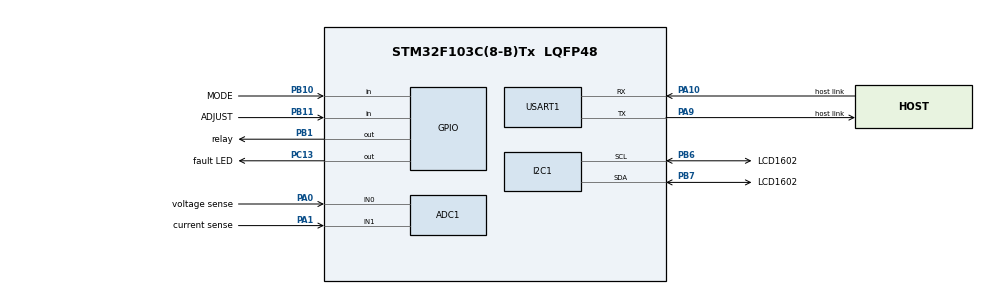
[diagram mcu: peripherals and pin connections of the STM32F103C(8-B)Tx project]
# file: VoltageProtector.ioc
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ADC1.Channel-1\#ChannelRegularConversion=ADC_CHANNEL_0
ADC1.NbrOfConversionFlag=1
ADC1.Rank-1\#ChannelRegularConversion=1
ADC1.SamplingTime-1\#ChannelRegularConversion=ADC_SAMPLETIME_1CYCLE_5
ADC1.master=1
Mcu.Family=STM32F1
Mcu.Name=STM32F103C(8-B)Tx
Mcu.Package=LQFP48
NVIC.PriorityGroup=NVIC_PRIORITYGROUP_4
NVIC.USART1_IRQn=true\:0\:0\:false\:false\:true\:true\:true\:true
PA0-WKUP.GPIO_Label=voltage sense
PA0-WKUP.Signal=ADCx_IN0
PA1.GPIO_Label=current sense
PA1.Signal=ADCx_IN1
PA10.GPIO_Label=host link
PA10.Mode=Asynchronous
PA10.Signal=USART1_RX
PA13.Mode=Serial_Wire
PA13.Signal=SYS_JTMS-SWDIO
PA14.Mode=Serial_Wire
PA14.Signal=SYS_JTCK-SWCLK
PA9.GPIO_Label=host link
PA9.Mode=Asynchronous
PA9.Signal=USART1_TX
PB1.GPIO_Label=relay
PB1.Signal=GPIO_Output
PB10.GPIO_Label=MODE
PB10.Signal=GPIO_Input
PB11.GPIO_Label=ADJUST
PB11.Signal=GPIO_Input
PB6.GPIO_Label=LCD1602
PB6.Mode=I2C
PB6.Signal=I2C1_SCL
PB7.GPIO_Label=LCD1602
PB7.Mode=I2C
PB7.Signal=I2C1_SDA
PC13-TAMPER-RTC.GPIO_Label=fault LED
PC13-TAMPER-RTC.Signal=GPIO_Output
PD0-OSC_IN.Mode=HSE-External-Oscillator
PD0-OSC_IN.Signal=RCC_OSC_IN
PD1-OSC_OUT.Mode=HSE-External-Oscillator
PD1-OSC_OUT.Signal=RCC_OSC_OUT
ProjectManager.HeapSize=0x200
ProjectManager.StackSize=0x400
ProjectManager.TargetToolchain=STM32CubeIDE
RCC.ADCPresc=RCC_ADCPCLK2_DIV6
RCC.AHBFreq_Value=72000000
RCC.APB1CLKDivider=RCC_HCLK_DIV2
RCC.APB1Freq_Value=36000000
RCC.APB1TimFreq_Value=72000000
RCC.APB2Freq_Value=72000000
RCC.APB2TimFreq_Value=72000000
RCC.HCLKFreq_Value=72000000
RCC.PLLMUL=RCC_PLL_MUL9
RCC.PLLSourceVirtual=RCC_PLLSOURCE_HSE
RCC.SYSCLKFreq_VALUE=72000000
RCC.SYSCLKSource=RCC_SYSCLKSOURCE_PLLCLK
RCC.USBFreq_Value=72000000
SH.ADCx_IN0.0=ADC1_IN0,IN0
SH.ADCx_IN1.0=ADC1_IN1,IN1
USART1.VirtualMode=VM_ASYNC
board=custom

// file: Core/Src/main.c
/* USER CODE BEGIN Header */
/**
  ******************************************************************************
  * @file           : main.c
  * @brief          : Main program body
  ******************************************************************************
  * @attention
  *
  * Copyright (c) 2026 STMicroelectronics.
  * All rights reserved.
  *
  * This software is licensed under terms that can be found in the LICENSE file
  * in the root directory of this software component.
  * If no LICENSE file comes with this software, it is provided AS-IS.
  *
  ******************************************************************************
  */
/* USER CODE END Header */
#include "main.h"
#include "adc.h"
#include "i2c.h"
#include "usart.h"
#include "gpio.h"

/* USER CODE BEGIN Includes */
#include "vp.h"
#include <stdio.h>
#include <string.h>
/* USER CODE END Includes */

void SystemClock_Config(void);

int main(void)
{

  /* MCU Configuration--------------------------------------------------------*/

  /* Reset of all peripherals, Initializes the Flash interface and the Systick. */
  HAL_Init();

  /* Configure the system clock */
  SystemClock_Config();

  /* Initialize all configured peripherals */
  MX_GPIO_Init();
  MX_ADC1_Init();
  MX_I2C1_Init();
  MX_USART1_UART_Init();
  /* USER CODE BEGIN 2 */
  {
    bool from_flash = vp_settings_load();
    vp_comms_init();
    vp_protection_init();
    vp_comms_printf("\r\n=== STM32 Voltage Protector ===\r\n");
    vp_comms_printf("SYSCLK=%lu Hz, sampling %u Hz, %u samples/cycle\r\n",
                    (unsigned long)HAL_RCC_GetSysClockFreq(),
                    VP_SAMPLE_HZ, VP_SAMPLES_CYCLE);
    vp_comms_printf("settings: %s\r\n", from_flash ? "restored from flash"
                    : (VP_AC_FRONTEND ? "defaults (AC front end)" : "defaults (DC pot demo)"));
    vp_comms_send_cfg();
    vp_ui_init();
  }
  /* USER CODE END 2 */

  /* Infinite loop */
  while (1)
  {

    /* USER CODE BEGIN 3 */
    {
      static uint32_t last_sample_ms, last_tele_ms;
      uint32_t now = HAL_GetTick();

      /* 1 kHz sampling, paced off the HAL tick */
      if (now != last_sample_ms) {
        last_sample_ms = now;
        vp_protection_sample();
      }
      if (vp_protection_cycle_ready()) {
        vp_protection_evaluate();
      }
      /* 10 Hz telemetry to the host */
      if (now - last_tele_ms >= 100u) {
        last_tele_ms = now;
        vp_comms_telemetry();
      }
      vp_comms_poll();
      vp_ui_poll(now);
    }
  }
  /* USER CODE END 3 */
}

void SystemClock_Config(void)
{
  RCC_OscInitTypeDef RCC_OscInitStruct = {0};
  RCC_ClkInitTypeDef RCC_ClkInitStruct = {0};
  RCC_PeriphCLKInitTypeDef PeriphClkInit = {0};

  /** Initializes the RCC Oscillators according to the specified parameters
  * in the RCC_OscInitTypeDef structure.
  */
#if PROTEUS_SIM
  /* Proteus VSM does not model the STM32F1 PLL: it runs the core from the raw
     HSE crystal regardless of PLL settings. Programming 72 MHz there makes HAL
     believe SystemCoreClock = 72 MHz while the silicon runs at 8 MHz, which
     scales every HAL_Delay and every measured trip time by 9x and puts the real
     UART bit rate at 12800 instead of 115200. So under simulation we run SYSCLK
     straight off the 8 MHz crystal, and HAL's timebase then matches reality. */
  RCC_OscInitStruct.OscillatorType = RCC_OSCILLATORTYPE_HSE;
  RCC_OscInitStruct.HSEState = RCC_HSE_ON;
  RCC_OscInitStruct.HSEPredivValue = RCC_HSE_PREDIV_DIV1;
  RCC_OscInitStruct.PLL.PLLState = RCC_PLL_NONE;
#else
  RCC_OscInitStruct.OscillatorType = RCC_OSCILLATORTYPE_HSE;
  RCC_OscInitStruct.HSEState = RCC_HSE_ON;
  RCC_OscInitStruct.HSEPredivValue = RCC_HSE_PREDIV_DIV1;
  RCC_OscInitStruct.HSIState = RCC_HSI_ON;
  RCC_OscInitStruct.PLL.PLLState = RCC_PLL_ON;
  RCC_OscInitStruct.PLL.PLLSource = RCC_PLLSOURCE_HSE;
  RCC_OscInitStruct.PLL.PLLMUL = RCC_PLL_MUL9;
#endif
  if (HAL_RCC_OscConfig(&RCC_OscInitStruct) != HAL_OK)
  {
    Error_Handler();
  }

  /** Initializes the CPU, AHB and APB buses clocks
  */
  RCC_ClkInitStruct.ClockType = RCC_CLOCKTYPE_HCLK|RCC_CLOCKTYPE_SYSCLK
                              |RCC_CLOCKTYPE_PCLK1|RCC_CLOCKTYPE_PCLK2;
#if PROTEUS_SIM
  RCC_ClkInitStruct.SYSCLKSource = RCC_SYSCLKSOURCE_HSE;      /* 8 MHz */
  RCC_ClkInitStruct.AHBCLKDivider = RCC_SYSCLK_DIV1;
  RCC_ClkInitStruct.APB1CLKDivider = RCC_HCLK_DIV1;           /* 8 MHz, <=36 */
  RCC_ClkInitStruct.APB2CLKDivider = RCC_HCLK_DIV1;           /* 8 MHz */

  if (HAL_RCC_ClockConfig(&RCC_ClkInitStruct, FLASH_LATENCY_0) != HAL_OK)
#else
  RCC_ClkInitStruct.SYSCLKSource = RCC_SYSCLKSOURCE_PLLCLK;
  RCC_ClkInitStruct.AHBCLKDivider = RCC_SYSCLK_DIV1;
  RCC_ClkInitStruct.APB1CLKDivider = RCC_HCLK_DIV2;
  RCC_ClkInitStruct.APB2CLKDivider = RCC_HCLK_DIV1;

  if (HAL_RCC_ClockConfig(&RCC_ClkInitStruct, FLASH_LATENCY_2) != HAL_OK)
#endif
  {
    Error_Handler();
  }
  PeriphClkInit.PeriphClockSelection = RCC_PERIPHCLK_ADC;
#if PROTEUS_SIM
  PeriphClkInit.AdcClockSelection = RCC_ADCPCLK2_DIV2;   /* 8/2 = 4 MHz  */
#else
  PeriphClkInit.AdcClockSelection = RCC_ADCPCLK2_DIV6;   /* 72/6 = 12 MHz */
#endif
  if (HAL_RCCEx_PeriphCLKConfig(&PeriphClkInit) != HAL_OK)
  {
    Error_Handler();
  }
}

void Error_Handler(void)
{
  __disable_irq();
  while (1)
  {
  }
}
